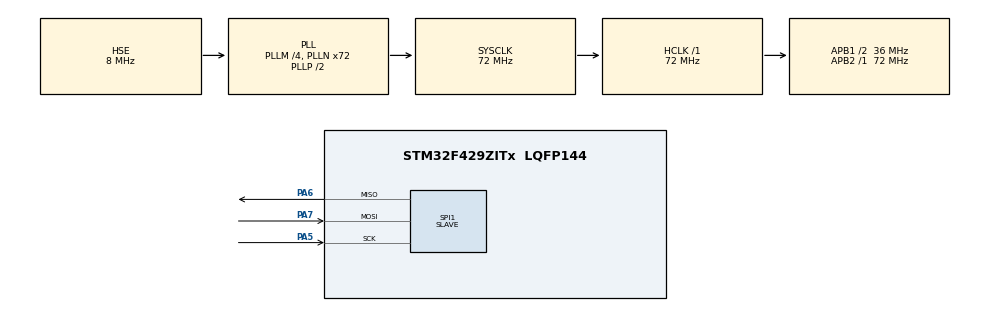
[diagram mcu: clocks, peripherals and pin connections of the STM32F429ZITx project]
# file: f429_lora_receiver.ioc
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Mcu.Family=STM32F4
RCC.PLLSourceVirtual=RCC_PLLSOURCE_HSE
PA6.Mode=Full_Duplex_Slave
RCC.CortexFreq_Value=72000000
PA7.Mode=Full_Duplex_Slave
SPI1.VirtualType=VM_SLAVE
RCC.APB1CLKDivider=RCC_HCLK_DIV2
RCC.SYSCLKSource=RCC_SYSCLKSOURCE_PLLCLK
ProjectManager.StackSize=0x400
ProjectManager.TargetToolchain=STM32CubeIDE
SPI1.Direction=SPI_DIRECTION_2LINES
PH0/OSC_IN.Mode=HSE-External-Oscillator
RCC.HCLKFreq_Value=72000000
RCC.APB2TimFreq_Value=72000000
PH1/OSC_OUT.Signal=RCC_OSC_OUT
RCC.LSE_VALUE=32768
RCC.AHBFreq_Value=72000000
PA5.Signal=SPI1_SCK
RCC.HSE_VALUE=8000000
board=STM32F429I-DISC1
RCC.VCOOutputFreq_Value=144000000
PH0/OSC_IN.Signal=RCC_OSC_IN
RCC.APB2Freq_Value=72000000
SPI1.Mode=SPI_MODE_SLAVE
PH1/OSC_OUT.Mode=HSE-External-Oscillator
Mcu.Name=STM32F429ZITx
RCC.48MHZClocksFreq_Value=48000000
RCC.SYSCLKFreq_VALUE=72000000
Mcu.Package=LQFP144
PA6.Signal=SPI1_MISO
ProjectManager.HeapSize=0x200
RCC.HSI_VALUE=16000000
RCC.PLLSAIN=50
RCC.PLLQ=3
NVIC.PriorityGroup=NVIC_PRIORITYGROUP_4
RCC.PLLM=4
RCC.PLLN=72
RCC.APB1TimFreq_Value=72000000
RCC.APB1Freq_Value=36000000
PA5.Mode=Full_Duplex_Slave
PA7.Signal=SPI1_MOSI

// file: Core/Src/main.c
/* USER CODE BEGIN Header */
/**
  ******************************************************************************
  * @file           : main.c
  * @brief          : Main program body
  ******************************************************************************
  * @attention
  *
  * <h2><center>&copy; Copyright (c) 2021 STMicroelectronics.
  * All rights reserved.</center></h2>
  *
  * This software component is licensed by ST under Ultimate Liberty license
  * SLA0044, the "License"; You may not use this file except in compliance with
  * the License. You may obtain a copy of the License at:
  *                             www.st.com/SLA0044
  *
  ******************************************************************************
  */
/* USER CODE END Header */
#include "main.h"
#include "stm32f4xx_hal.h"
#include "mainApp.h"

SPI_HandleTypeDef hspi1;

void SystemClock_Config(void);
static void MX_GPIO_Init(void);
static void MX_SPI1_Init(void);

int main(void)
{

  /* MCU Configuration--------------------------------------------------------*/

  /* Reset of all peripherals, Initializes the Flash interface and the Systick. */
  HAL_Init();

  /* Configure the system clock */
  SystemClock_Config();

  /* Initialize all configured peripherals */
  MX_GPIO_Init();
  MX_SPI1_Init();

  /* Infinite loop */
  while (1)
  {
	  mainApp();
  }
}

void SystemClock_Config(void)
{
  RCC_OscInitTypeDef RCC_OscInitStruct = {0};
  RCC_ClkInitTypeDef RCC_ClkInitStruct = {0};

  /** Configure the main internal regulator output voltage
  */
  __HAL_RCC_PWR_CLK_ENABLE();
  __HAL_PWR_VOLTAGESCALING_CONFIG(PWR_REGULATOR_VOLTAGE_SCALE3);
  /** Initializes the RCC Oscillators according to the specified parameters
  * in the RCC_OscInitTypeDef structure.
  */
  RCC_OscInitStruct.OscillatorType = RCC_OSCILLATORTYPE_HSE;
  RCC_OscInitStruct.HSEState = RCC_HSE_ON;
  RCC_OscInitStruct.PLL.PLLState = RCC_PLL_ON;
  RCC_OscInitStruct.PLL.PLLSource = RCC_PLLSOURCE_HSE;
  RCC_OscInitStruct.PLL.PLLM = 4;
  RCC_OscInitStruct.PLL.PLLN = 72;
  RCC_OscInitStruct.PLL.PLLP = RCC_PLLP_DIV2;
  RCC_OscInitStruct.PLL.PLLQ = 3;
  if (HAL_RCC_OscConfig(&RCC_OscInitStruct) != HAL_OK)
  {
    Error_Handler();
  }
  /** Initializes the CPU, AHB and APB buses clocks
  */
  RCC_ClkInitStruct.ClockType = RCC_CLOCKTYPE_HCLK|RCC_CLOCKTYPE_SYSCLK
                              |RCC_CLOCKTYPE_PCLK1|RCC_CLOCKTYPE_PCLK2;
  RCC_ClkInitStruct.SYSCLKSource = RCC_SYSCLKSOURCE_PLLCLK;
  RCC_ClkInitStruct.AHBCLKDivider = RCC_SYSCLK_DIV1;
  RCC_ClkInitStruct.APB1CLKDivider = RCC_HCLK_DIV2;
  RCC_ClkInitStruct.APB2CLKDivider = RCC_HCLK_DIV1;

  if (HAL_RCC_ClockConfig(&RCC_ClkInitStruct, FLASH_LATENCY_2) != HAL_OK)
  {
    Error_Handler();
  }

  /**Configure the Systick interrupt time
  */
HAL_SYSTICK_Config(HAL_RCC_GetHCLKFreq()/1000);

  /**Configure the Systick
  */
HAL_SYSTICK_CLKSourceConfig(SYSTICK_CLKSOURCE_HCLK);

/* SysTick_IRQn interrupt configuration */
HAL_NVIC_SetPriority(SysTick_IRQn, 0, 0);
}

static void MX_SPI1_Init(void)
{

  /* SPI1 parameter configuration*/
  hspi1.Instance = SPI1;
  hspi1.Init.Mode = SPI_MODE_MASTER;
  hspi1.Init.Direction = SPI_DIRECTION_2LINES;
  hspi1.Init.DataSize = SPI_DATASIZE_8BIT;
  hspi1.Init.CLKPolarity = SPI_POLARITY_LOW;
  hspi1.Init.CLKPhase = SPI_PHASE_1EDGE;
  hspi1.Init.NSS = SPI_NSS_SOFT;
  hspi1.Init.BaudRatePrescaler = SPI_BAUDRATEPRESCALER_256;
  hspi1.Init.FirstBit = SPI_FIRSTBIT_MSB;
  hspi1.Init.TIMode = SPI_TIMODE_DISABLE;
  hspi1.Init.CRCCalculation = SPI_CRCCALCULATION_DISABLE;
  hspi1.Init.CRCPolynomial = 10;
  if (HAL_SPI_Init(&hspi1) != HAL_OK)
  {
    Error_Handler();
  }

}

static void MX_GPIO_Init(void)
{

  GPIO_InitTypeDef GPIO_InitStruct;

  /* GPIO Ports Clock Enable */
  __HAL_RCC_GPIOG_CLK_ENABLE();
  __HAL_RCC_GPIOC_CLK_ENABLE();
  __HAL_RCC_GPIOA_CLK_ENABLE();

  /*Configure GPIO pin Output Level */
    HAL_GPIO_WritePin(RED_LED_GPIO_Port, RED_LED_Pin, GPIO_PIN_RESET);

    /*Configure GPIO pin Output Level */
    HAL_GPIO_WritePin(GPIOA, Reset_Pin|nIrq_Pin|DIO1_Pin|SPI_NSS_Pin, GPIO_PIN_RESET);

    /*Configure GPIO pin : RED_LED_Pin */
    GPIO_InitStruct.Pin = RED_LED_Pin;
    GPIO_InitStruct.Mode = GPIO_MODE_OUTPUT_PP;
    GPIO_InitStruct.Speed = GPIO_SPEED_FREQ_LOW;
    HAL_GPIO_Init(RED_LED_GPIO_Port, &GPIO_InitStruct);

    /*Configure GPIO pins : Reset_Pin nIrq_Pin DIO1_Pin SPI_NSS_Pin */
    GPIO_InitStruct.Pin = Reset_Pin|nIrq_Pin|DIO1_Pin|SPI_NSS_Pin;
    GPIO_InitStruct.Mode = GPIO_MODE_OUTPUT_PP;
    GPIO_InitStruct.Speed = GPIO_SPEED_FREQ_LOW;
    HAL_GPIO_Init(GPIOA, &GPIO_InitStruct);

}

void Error_Handler(void)
{
  __disable_irq();
  while (1)
  {
  }
}

/************************ (C) COPYRIGHT STMicroelectronics *****END OF FILE****/
